VERSION 5.8 ;
BUSBITCHARS "[]" ;
DIVIDERCHAR "/" ;

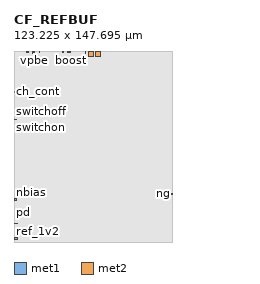
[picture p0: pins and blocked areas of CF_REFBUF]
MACRO CF_REFBUF
  ORIGIN 0 0 ;
  FOREIGN CF_REFBUF 0 0 ;
  SIZE 123.225 BY 147.695 ;
  PIN nbias
    DIRECTION INPUT ;
    USE SIGNAL ;
    PORT
      LAYER met1 ;
        RECT 0 32.44 1.59 33.51 ;
    END
  END nbias
  PIN out
    DIRECTION OUTPUT ;
    USE SIGNAL ;
    PORT
      LAYER met2 ;
        RECT 58.015 144.05 61.545 147.695 ;
    END
  END out
  PIN switchoff
    DIRECTION OUTPUT ;
    USE SIGNAL ;
    PORT
      LAYER met2 ;
        RECT 0 94.925 1.95 95.47 ;
    END
  END switchoff
  PIN ref_1v2
    DIRECTION INPUT ;
    USE SIGNAL ;
    PORT
      LAYER met2 ;
        RECT 0 14.02 2.935 14.685 ;
    END
  END ref_1v2
  PIN vnb
    DIRECTION INPUT ;
    USE GROUND ;
    PORT
      LAYER met2 ;
        RECT 55.295 146.48 55.8 147.695 ;
    END
  END vnb
  PIN vpb
    DIRECTION INPUT ;
    USE POWER ;
    PORT
      LAYER met2 ;
        RECT 19.515 146.95 20.155 147.695 ;
    END
  END vpb
  PIN vpbe
    DIRECTION INPUT ;
    USE POWER ;
    PORT
      LAYER met1 ;
        RECT 15.28 147.11 16.005 147.695 ;
    END
  END vpbe
  PIN vgnd
    DIRECTION INPUT ;
    USE GROUND ;
    PORT
      LAYER met2 ;
        RECT 41.935 147.035 43.265 147.695 ;
    END
  END vgnd
  PIN pd
    DIRECTION INPUT ;
    USE SIGNAL ;
    PORT
      LAYER met1 ;
        RECT 0 22.595 0.655 22.915 ;
    END
  END pd
  PIN ng
    DIRECTION INPUT ;
    USE POWER ;
    PORT
      LAYER met2 ;
        RECT 122.05 37.09 123.225 38.055 ;
    END
  END ng
  PIN switchon
    DIRECTION INPUT ;
    USE SIGNAL ;
    PORT
      LAYER met1 ;
        RECT 17.335 88.87 17.85 89.42 ;
      LAYER met2 ;
        RECT 37.9 147.075 38.25 147.695 ;
    END
  END switchon
  PIN ch_cont
    DIRECTION INPUT ;
    USE SIGNAL ;
    PORT
      LAYER met1 ;
        RECT 0 116.395 1.1 117.075 ;
    END
  END ch_cont
  PIN boost
    DIRECTION INPUT ;
    USE SIGNAL ;
    PORT
      LAYER met2 ;
        RECT 43.775 147.18 44.125 147.695 ;
    END
  END boost
  PIN vpwre
    DIRECTION INPUT ;
    USE POWER ;
    PORT
      LAYER met2 ;
        RECT 63.33 144.355 67.215 147.695 ;
    END
  END vpwre
  PIN ch2
    DIRECTION INPUT ;
    USE SIGNAL ;
    PORT
      LAYER met2 ;
        RECT 10.01 147.095 10.97 147.695 ;
    END
  END ch2
  PIN vpwr
    DIRECTION INPUT ;
    USE POWER ;
    PORT
      LAYER met1 ;
        RECT 0 1.94 2.655 3.31 ;
    END
  END vpwr
  PIN ch1
    DIRECTION INPUT ;
    USE SIGNAL ;
    PORT
      LAYER met1 ;
        RECT 14.355 146.54 14.755 147.695 ;
    END
  END ch1
  OBS
    LAYER li1 ;
      RECT 0 0 123.225 147.695 ;
    LAYER met1 ;
      RECT 0 0 0.655 1.94 ;
      RECT 0 3.31 0.655 22.595 ;
      RECT 0 22.915 0.655 32.44 ;
      RECT 0 33.51 0.655 116.395 ;
      RECT 0 117.075 0.655 147.695 ;
      RECT 0.655 0 1.1 1.94 ;
      RECT 0.655 3.31 1.1 32.44 ;
      RECT 0.655 33.51 1.1 116.395 ;
      RECT 0.655 117.075 1.1 147.695 ;
      RECT 1.1 0 1.59 1.94 ;
      RECT 1.1 3.31 1.59 32.44 ;
      RECT 1.1 33.51 1.59 147.695 ;
      RECT 1.59 0 2.655 1.94 ;
      RECT 1.59 3.31 2.655 147.695 ;
      RECT 2.655 0 14.355 147.695 ;
      RECT 14.355 0 14.755 146.54 ;
      RECT 14.755 0 15.28 147.695 ;
      RECT 15.28 0 16.005 147.11 ;
      RECT 16.005 0 17.335 147.695 ;
      RECT 17.335 0 17.85 88.87 ;
      RECT 17.335 89.42 17.85 147.695 ;
      RECT 17.85 0 123.225 147.695 ;
    LAYER met2 ;
      RECT 0 0 1.95 14.02 ;
      RECT 0 14.685 1.95 94.925 ;
      RECT 0 95.47 1.95 147.695 ;
      RECT 1.95 0 2.935 14.02 ;
      RECT 1.95 14.685 2.935 147.695 ;
      RECT 2.935 0 10.01 147.695 ;
      RECT 10.01 0 10.97 147.095 ;
      RECT 10.97 0 19.515 147.695 ;
      RECT 19.515 0 20.155 146.95 ;
      RECT 20.155 0 37.9 147.695 ;
      RECT 37.9 0 38.25 147.075 ;
      RECT 38.25 0 41.935 147.695 ;
      RECT 41.935 0 43.265 147.035 ;
      RECT 43.265 0 43.775 147.695 ;
      RECT 43.775 0 44.125 147.18 ;
      RECT 44.125 0 55.295 147.695 ;
      RECT 55.295 0 55.8 146.48 ;
      RECT 55.8 0 58.015 147.695 ;
      RECT 58.015 0 61.545 144.05 ;
      RECT 61.545 0 63.33 147.695 ;
      RECT 63.33 0 67.215 144.355 ;
      RECT 67.215 0 122.05 147.695 ;
      RECT 122.05 0 123.225 37.09 ;
      RECT 122.05 38.055 123.225 147.695 ;
    LAYER met3 ;
      RECT 0 0 123.225 147.695 ;
  END
END CF_REFBUF

END LIBRARY
